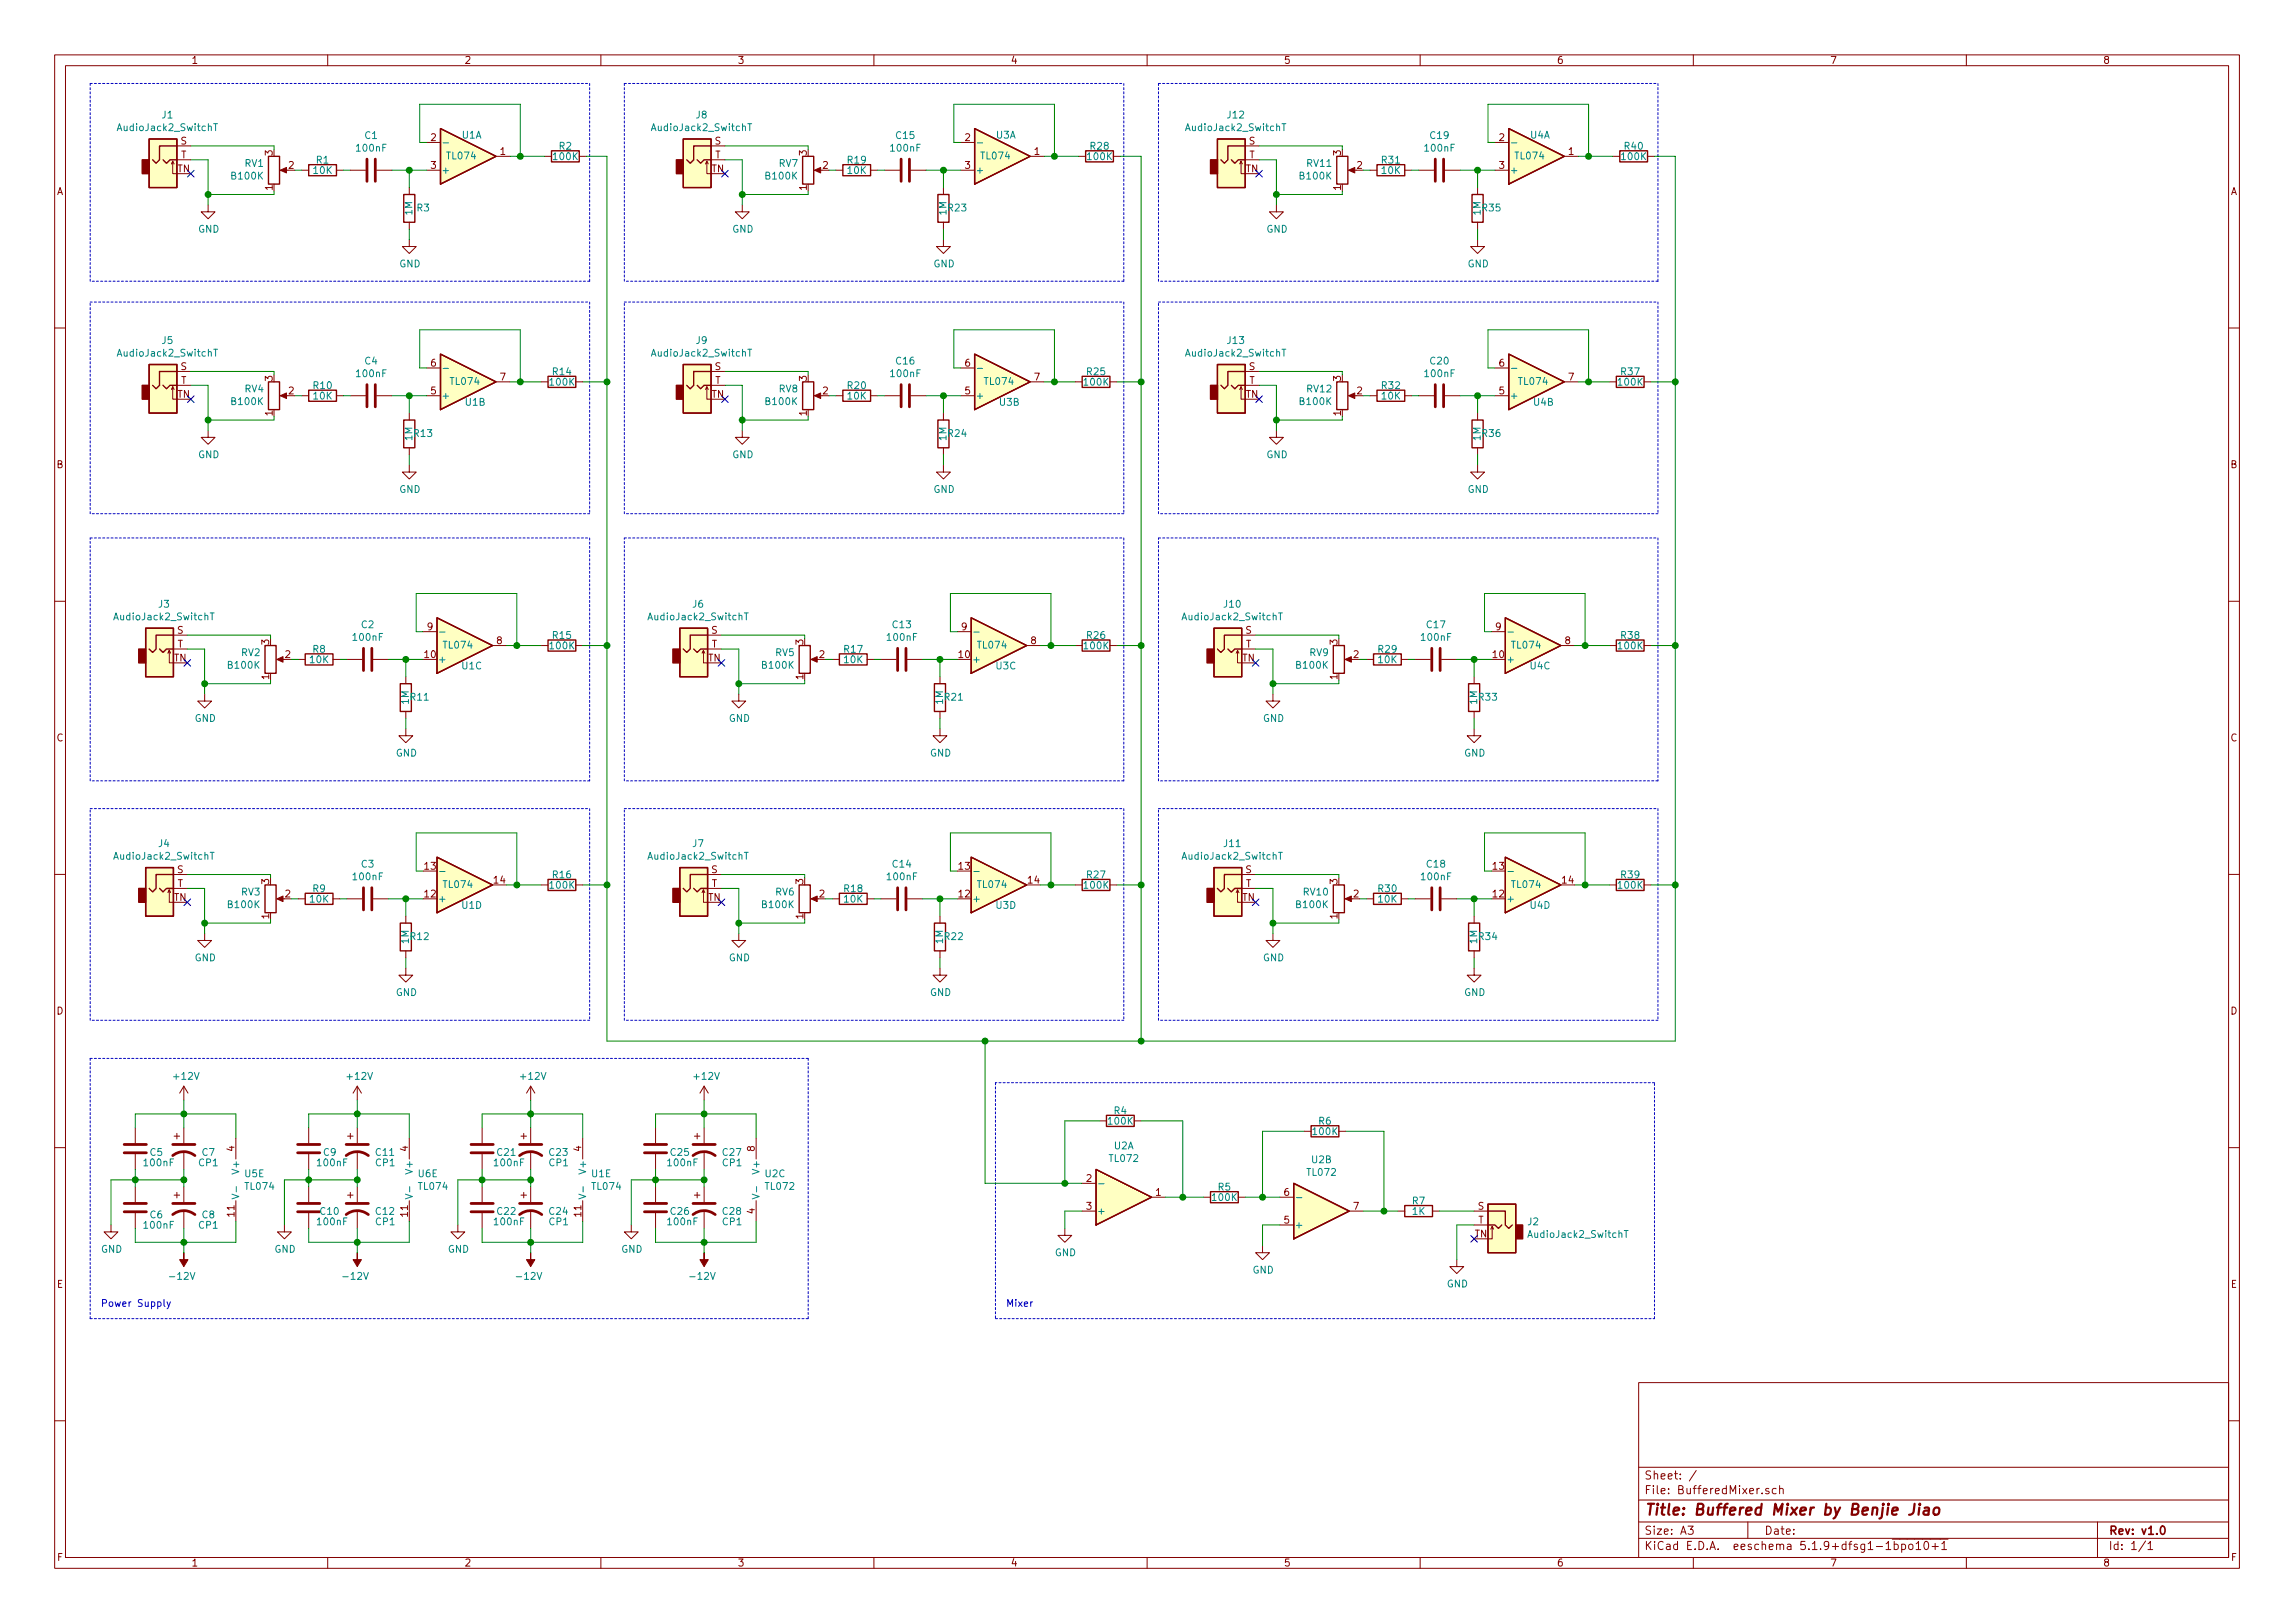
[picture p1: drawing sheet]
<svg xmlns="http://www.w3.org/2000/svg" width="420mm" height="297mm" viewBox="0 0 420 297" stroke-linecap="round" stroke-linejoin="round" font-family="sans-serif">
<defs><g id="words">
<text font-size="2.8" fill="#840000" x="301" y="277.3">Title: Buffered Mixer by Benjie Jiao</text>
<g font-size="2.1" fill="#840000">
<text x="301" y="273.5">File: BufferedMixer.sch</text>
<text x="301" y="270.8">Sheet: /</text>
<text x="301" y="280.9">Size: A3</text>
<text x="323" y="280.9">Date:</text>
<text x="386" y="280.9">Rev: v1.0</text>
<text x="301" y="283.7">KiCad E.D.A. eeschema 5.1.9+dfsg1-1bpo10+1</text>
<text x="386" y="283.7">Id: 1/1</text>
</g>
<g font-size="1.8" fill="#840000">
<text x="35" y="11.7">1</text>
<text x="85" y="11.7">2</text>
<text x="135" y="11.7">3</text>
<text x="185" y="11.7">4</text>
<text x="235" y="11.7">5</text>
<text x="285" y="11.7">6</text>
<text x="335" y="11.7">7</text>
<text x="385" y="11.7">8</text>
<text x="33.1" y="26.5">S</text>
<text x="33.1" y="29">T</text>
<text x="49.9" y="28.5" transform="rotate(-90 49.9 28.5)">3</text>
<text x="78.9" y="25.8">2</text>
<text x="91.6" y="28.4">1</text>
<text x="130.9" y="26.5">S</text>
<text x="130.9" y="29">T</text>
<text x="147.7" y="28.5" transform="rotate(-90 147.7 28.5)">3</text>
<text x="176.7" y="25.8">2</text>
<text x="189.4" y="28.4">1</text>
<text x="228.7" y="26.5">S</text>
<text x="228.7" y="29">T</text>
<text x="245.5" y="28.5" transform="rotate(-90 245.5 28.5)">3</text>
<text x="274.5" y="25.8">2</text>
<text x="287.2" y="28.4">1</text>
<text x="10.4" y="35.7">A</text>
<text x="32.5" y="31.5">TN</text>
<text x="49.9" y="34.8" transform="rotate(-90 49.9 34.8)">1</text>
<text x="52.9" y="30.9">2</text>
<text x="78.9" y="30.9">3</text>
<text x="130.3" y="31.5">TN</text>
<text x="147.7" y="34.8" transform="rotate(-90 147.7 34.8)">1</text>
<text x="150.6" y="30.9">2</text>
<text x="176.7" y="30.9">3</text>
<text x="228.1" y="31.5">TN</text>
<text x="245.5" y="34.8" transform="rotate(-90 245.5 34.8)">1</text>
<text x="248.4" y="30.9">2</text>
<text x="274.5" y="30.9">3</text>
<text x="408.4" y="35.7">A</text>
<text x="33.1" y="67.7">S</text>
<text x="33.1" y="70.3">T</text>
<text x="49.9" y="69.7" transform="rotate(-90 49.9 69.7)">3</text>
<text x="78.9" y="67.1">6</text>
<text x="91.6" y="69.6">7</text>
<text x="130.9" y="67.7">S</text>
<text x="130.9" y="70.3">T</text>
<text x="147.7" y="69.7" transform="rotate(-90 147.7 69.7)">3</text>
<text x="176.7" y="67.1">6</text>
<text x="189.4" y="69.6">7</text>
<text x="228.7" y="67.7">S</text>
<text x="228.7" y="70.3">T</text>
<text x="245.5" y="69.7" transform="rotate(-90 245.5 69.7)">3</text>
<text x="274.5" y="67.1">6</text>
<text x="287.2" y="69.6">7</text>
<text x="32.5" y="72.8">TN</text>
<text x="49.9" y="76.1" transform="rotate(-90 49.9 76.1)">1</text>
<text x="52.9" y="72.2">2</text>
<text x="78.9" y="72.2">5</text>
<text x="130.3" y="72.8">TN</text>
<text x="147.7" y="76.1" transform="rotate(-90 147.7 76.1)">1</text>
<text x="150.6" y="72.2">2</text>
<text x="176.7" y="72.2">5</text>
<text x="228.1" y="72.8">TN</text>
<text x="245.5" y="76.1" transform="rotate(-90 245.5 76.1)">1</text>
<text x="248.4" y="72.2">2</text>
<text x="274.5" y="72.2">5</text>
<text x="10.4" y="85.7">B</text>
<text x="408.4" y="85.7">B</text>
<text x="32.4" y="116">S</text>
<text x="32.5" y="118.5">T</text>
<text x="49.3" y="118" transform="rotate(-90 49.3 118)">3</text>
<text x="78.3" y="115.4">9</text>
<text x="91" y="117.9">8</text>
<text x="130.2" y="116">S</text>
<text x="130.3" y="118.5">T</text>
<text x="147.1" y="118" transform="rotate(-90 147.1 118)">3</text>
<text x="176" y="115.4">9</text>
<text x="188.7" y="117.9">8</text>
<text x="228" y="116">S</text>
<text x="228.1" y="118.5">T</text>
<text x="244.9" y="118" transform="rotate(-90 244.9 118)">3</text>
<text x="273.8" y="115.4">9</text>
<text x="286.5" y="117.9">8</text>
<text x="31.9" y="121.1">TN</text>
<text x="49.3" y="124.3" transform="rotate(-90 49.3 124.3)">1</text>
<text x="52.2" y="120.4">2</text>
<text x="77.8" y="120.4">10</text>
<text x="129.6" y="121.1">TN</text>
<text x="147.1" y="124.3" transform="rotate(-90 147.1 124.3)">1</text>
<text x="150" y="120.4">2</text>
<text x="175.6" y="120.4">10</text>
<text x="227.4" y="121.1">TN</text>
<text x="244.9" y="124.3" transform="rotate(-90 244.9 124.3)">1</text>
<text x="247.8" y="120.4">2</text>
<text x="273.4" y="120.4">10</text>
<text x="10.4" y="135.7">C</text>
<text x="408.4" y="135.7">C</text>
<text x="32.4" y="159.8">S</text>
<text x="49.3" y="161.8" transform="rotate(-90 49.3 161.8)">3</text>
<text x="77.8" y="159.2">13</text>
<text x="90.5" y="161.7">14</text>
<text x="130.2" y="159.8">S</text>
<text x="147.1" y="161.8" transform="rotate(-90 147.1 161.8)">3</text>
<text x="175.6" y="159.2">13</text>
<text x="188.3" y="161.7">14</text>
<text x="228" y="159.8">S</text>
<text x="244.9" y="161.8" transform="rotate(-90 244.9 161.8)">3</text>
<text x="273.4" y="159.2">13</text>
<text x="286.1" y="161.7">14</text>
<text x="31.9" y="164.9">TN</text>
<text x="32.5" y="162.3">T</text>
<text x="52.2" y="164.2">2</text>
<text x="77.8" y="164.2">12</text>
<text x="129.6" y="164.9">TN</text>
<text x="130.3" y="162.3">T</text>
<text x="150" y="164.2">2</text>
<text x="175.6" y="164.2">12</text>
<text x="227.4" y="164.9">TN</text>
<text x="228.1" y="162.3">T</text>
<text x="247.8" y="164.2">2</text>
<text x="273.4" y="164.2">12</text>
<text x="49.3" y="168.2" transform="rotate(-90 49.3 168.2)">1</text>
<text x="147.1" y="168.2" transform="rotate(-90 147.1 168.2)">1</text>
<text x="244.9" y="168.2" transform="rotate(-90 244.9 168.2)">1</text>
<text x="10.4" y="185.7">D</text>
<text x="408.4" y="185.7">D</text>
<text x="42.9" y="210.7" transform="rotate(-90 42.9 210.7)">4</text>
<text x="74.7" y="210.7" transform="rotate(-90 74.7 210.7)">4</text>
<text x="106.4" y="210.7" transform="rotate(-90 106.4 210.7)">4</text>
<text x="138.2" y="210.7" transform="rotate(-90 138.2 210.7)">8</text>
<text x="198.9" y="216.3">2</text>
<text x="198.9" y="221.4">3</text>
<text x="211.6" y="218.9">1</text>
<text x="235.1" y="218.9">6</text>
<text x="247.8" y="221.4">7</text>
<text x="270.6" y="221.4">S</text>
<text x="42.9" y="222.6" transform="rotate(-90 42.9 222.6)">11</text>
<text x="74.7" y="222.6" transform="rotate(-90 74.7 222.6)">11</text>
<text x="106.4" y="222.6" transform="rotate(-90 106.4 222.6)">11</text>
<text x="138.2" y="222.1" transform="rotate(-90 138.2 222.1)">4</text>
<text x="235.1" y="223.9">5</text>
<text x="270" y="226.5">TN</text>
<text x="270.6" y="223.9">T</text>
<text x="10.4" y="235.7">E</text>
<text x="408.4" y="235.7">E</text>
<text x="10.5" y="285.7">F</text>
<text x="35" y="286.7">1</text>
<text x="85" y="286.7">2</text>
<text x="135" y="286.7">3</text>
<text x="185" y="286.7">4</text>
<text x="235" y="286.7">5</text>
<text x="285" y="286.7">6</text>
<text x="335" y="286.7">7</text>
<text x="385" y="286.7">8</text>
<text x="408.5" y="285.7">F</text>
</g>
<g font-size="1.8" fill="#008484">
<text x="21.8" y="24">AudioJack2_SwitchT</text>
<text x="29.7" y="21.7">J1</text>
<text x="119.6" y="24">AudioJack2_SwitchT</text>
<text x="127.5" y="21.7">J8</text>
<text x="217.4" y="24">AudioJack2_SwitchT</text>
<text x="224.8" y="21.7">J12</text>
<text x="57.9" y="29.9">R1</text>
<text x="65.4" y="27.7">100nF</text>
<text x="66.8" y="25.4">C1</text>
<text x="81.9" y="29.2">TL074</text>
<text x="84.6" y="25.4">U1A</text>
<text x="101.4" y="29.3">100K</text>
<text x="102.4" y="27.4">R2</text>
<text x="155.2" y="29.9">R19</text>
<text x="163.2" y="27.7">100nF</text>
<text x="164.1" y="25.4">C15</text>
<text x="179.7" y="29.2">TL074</text>
<text x="182.4" y="25.4">U3A</text>
<text x="199.2" y="29.3">100K</text>
<text x="199.7" y="27.4">R28</text>
<text x="253" y="29.9">R31</text>
<text x="261" y="27.7">100nF</text>
<text x="261.9" y="25.4">C19</text>
<text x="277.5" y="29.2">TL074</text>
<text x="280.2" y="25.4">U4A</text>
<text x="297" y="29.3">100K</text>
<text x="297.5" y="27.4">R40</text>
<text x="42.5" y="32.9">B100K</text>
<text x="44.9" y="30.5">RV1</text>
<text x="57.4" y="31.8">10K</text>
<text x="80.8" y="31.8">+</text>
<text x="140.3" y="32.9">B100K</text>
<text x="142.6" y="30.5">RV7</text>
<text x="155.2" y="31.8">10K</text>
<text x="178.6" y="31.8">+</text>
<text x="238.1" y="32.9">B100K</text>
<text x="239.3" y="30.5">RV11</text>
<text x="253" y="31.8">10K</text>
<text x="276.4" y="31.8">+</text>
<text x="75.5" y="39.4" transform="rotate(-90 75.5 39.4)">1M</text>
<text x="76.4" y="38.7">R3</text>
<text x="173.3" y="39.4" transform="rotate(-90 173.3 39.4)">1M</text>
<text x="173.6" y="38.7">R23</text>
<text x="271.1" y="39.4" transform="rotate(-90 271.1 39.4)">1M</text>
<text x="271.4" y="38.7">R35</text>
<text x="36.3" y="42.6">GND</text>
<text x="134.1" y="42.6">GND</text>
<text x="231.9" y="42.6">GND</text>
<text x="73.1" y="48.9">GND</text>
<text x="170.9" y="48.9">GND</text>
<text x="268.7" y="48.9">GND</text>
<text x="21.8" y="65.3">AudioJack2_SwitchT</text>
<text x="29.7" y="63">J5</text>
<text x="119.6" y="65.3">AudioJack2_SwitchT</text>
<text x="127.5" y="63">J9</text>
<text x="217.4" y="65.3">AudioJack2_SwitchT</text>
<text x="224.8" y="63">J13</text>
<text x="44.9" y="71.8">RV4</text>
<text x="57.4" y="71.2">R10</text>
<text x="65.4" y="69">100nF</text>
<text x="66.8" y="66.7">C4</text>
<text x="82.5" y="70.4">TL074</text>
<text x="100.8" y="70.6">100K</text>
<text x="101.2" y="68.7">R14</text>
<text x="142.6" y="71.8">RV8</text>
<text x="155.2" y="71.2">R20</text>
<text x="163.2" y="69">100nF</text>
<text x="164.1" y="66.7">C16</text>
<text x="180.3" y="70.4">TL074</text>
<text x="198.6" y="70.6">100K</text>
<text x="199" y="68.7">R25</text>
<text x="239.3" y="71.8">RV12</text>
<text x="253" y="71.2">R32</text>
<text x="261" y="69">100nF</text>
<text x="261.9" y="66.7">C20</text>
<text x="278.1" y="70.4">TL074</text>
<text x="296.3" y="70.6">100K</text>
<text x="296.8" y="68.7">R37</text>
<text x="42.5" y="74.1">B100K</text>
<text x="57.4" y="73.1">10K</text>
<text x="80.8" y="73.1">+</text>
<text x="85.2" y="74.3">U1B</text>
<text x="140.3" y="74.1">B100K</text>
<text x="155.2" y="73.1">10K</text>
<text x="178.6" y="73.1">+</text>
<text x="183" y="74.3">U3B</text>
<text x="238.1" y="74.1">B100K</text>
<text x="253" y="73.1">10K</text>
<text x="276.4" y="73.1">+</text>
<text x="280.8" y="74.3">U4B</text>
<text x="36.3" y="83.9">GND</text>
<text x="75.5" y="80.6" transform="rotate(-90 75.5 80.6)">1M</text>
<text x="75.8" y="80">R13</text>
<text x="134.1" y="83.9">GND</text>
<text x="173.3" y="80.6" transform="rotate(-90 173.3 80.6)">1M</text>
<text x="173.6" y="80">R24</text>
<text x="231.9" y="83.9">GND</text>
<text x="271.1" y="80.6" transform="rotate(-90 271.1 80.6)">1M</text>
<text x="271.4" y="80">R36</text>
<text x="73.1" y="90.2">GND</text>
<text x="170.9" y="90.2">GND</text>
<text x="268.7" y="90.2">GND</text>
<text x="21.2" y="113.5">AudioJack2_SwitchT</text>
<text x="29.1" y="111.2">J3</text>
<text x="119" y="113.5">AudioJack2_SwitchT</text>
<text x="126.8" y="111.2">J6</text>
<text x="216.8" y="113.5">AudioJack2_SwitchT</text>
<text x="224.1" y="111.2">J10</text>
<text x="57.3" y="119.5">R8</text>
<text x="64.8" y="117.3">100nF</text>
<text x="66.2" y="115">C2</text>
<text x="81.3" y="118.7">TL074</text>
<text x="100.8" y="118.8">100K</text>
<text x="101.2" y="116.9">R15</text>
<text x="154.6" y="119.5">R17</text>
<text x="162.6" y="117.3">100nF</text>
<text x="163.5" y="115">C13</text>
<text x="179.1" y="118.7">TL074</text>
<text x="198.6" y="118.8">100K</text>
<text x="199" y="116.9">R26</text>
<text x="252.4" y="119.5">R29</text>
<text x="260.3" y="117.3">100nF</text>
<text x="261.3" y="115">C17</text>
<text x="276.9" y="118.7">TL074</text>
<text x="296.3" y="118.8">100K</text>
<text x="296.8" y="116.9">R38</text>
<text x="41.9" y="122.4">B100K</text>
<text x="44.2" y="120.1">RV2</text>
<text x="56.8" y="121.4">10K</text>
<text x="80.1" y="121.3">+</text>
<text x="84.6" y="122.5">U1C</text>
<text x="139.6" y="122.4">B100K</text>
<text x="142" y="120.1">RV5</text>
<text x="154.6" y="121.4">10K</text>
<text x="177.9" y="121.3">+</text>
<text x="182.4" y="122.5">U3C</text>
<text x="237.4" y="122.4">B100K</text>
<text x="239.8" y="120.1">RV9</text>
<text x="252.4" y="121.4">10K</text>
<text x="275.7" y="121.3">+</text>
<text x="280.2" y="122.5">U4C</text>
<text x="74.9" y="128.9" transform="rotate(-90 74.9 128.9)">1M</text>
<text x="75.2" y="128.2">R11</text>
<text x="172.6" y="128.9" transform="rotate(-90 172.6 128.9)">1M</text>
<text x="173" y="128.2">R21</text>
<text x="270.4" y="128.9" transform="rotate(-90 270.4 128.9)">1M</text>
<text x="270.8" y="128.2">R33</text>
<text x="35.6" y="132.1">GND</text>
<text x="133.4" y="132.1">GND</text>
<text x="231.2" y="132.1">GND</text>
<text x="72.5" y="138.5">GND</text>
<text x="170.3" y="138.5">GND</text>
<text x="268" y="138.5">GND</text>
<text x="29.1" y="155">J4</text>
<text x="126.8" y="155">J7</text>
<text x="224.1" y="155">J11</text>
<text x="21.2" y="157.3">AudioJack2_SwitchT</text>
<text x="64.8" y="161.1">100nF</text>
<text x="66.2" y="158.8">C3</text>
<text x="101.2" y="160.7">R16</text>
<text x="119" y="157.3">AudioJack2_SwitchT</text>
<text x="162.6" y="161.1">100nF</text>
<text x="163.5" y="158.8">C14</text>
<text x="199" y="160.7">R27</text>
<text x="216.8" y="157.3">AudioJack2_SwitchT</text>
<text x="260.3" y="161.1">100nF</text>
<text x="261.3" y="158.8">C18</text>
<text x="296.8" y="160.7">R39</text>
<text x="41.9" y="166.2">B100K</text>
<text x="44.2" y="163.9">RV3</text>
<text x="56.8" y="165.2">10K</text>
<text x="57.3" y="163.3">R9</text>
<text x="80.1" y="165.1">+</text>
<text x="81.3" y="162.5">TL074</text>
<text x="84.6" y="166.3">U1D</text>
<text x="100.8" y="162.6">100K</text>
<text x="139.6" y="166.2">B100K</text>
<text x="142" y="163.9">RV6</text>
<text x="154.6" y="163.3">R18</text>
<text x="154.6" y="165.2">10K</text>
<text x="177.9" y="165.1">+</text>
<text x="179.1" y="162.5">TL074</text>
<text x="182.4" y="166.3">U3D</text>
<text x="198.6" y="162.6">100K</text>
<text x="237.4" y="166.2">B100K</text>
<text x="238.7" y="163.9">RV10</text>
<text x="252.4" y="163.3">R30</text>
<text x="252.4" y="165.2">10K</text>
<text x="275.7" y="165.1">+</text>
<text x="276.9" y="162.5">TL074</text>
<text x="280.2" y="166.3">U4D</text>
<text x="296.3" y="162.6">100K</text>
<text x="74.9" y="172.7" transform="rotate(-90 74.9 172.7)">1M</text>
<text x="75.2" y="172">R12</text>
<text x="172.6" y="172.7" transform="rotate(-90 172.6 172.7)">1M</text>
<text x="173" y="172">R22</text>
<text x="270.4" y="172.7" transform="rotate(-90 270.4 172.7)">1M</text>
<text x="270.8" y="172">R34</text>
<text x="35.6" y="175.9">GND</text>
<text x="133.4" y="175.9">GND</text>
<text x="231.2" y="175.9">GND</text>
<text x="72.5" y="182.3">GND</text>
<text x="170.3" y="182.3">GND</text>
<text x="268" y="182.3">GND</text>
<text x="32" y="197.6">+12V</text>
<text x="63.7" y="197.6">+12V</text>
<text x="95.5" y="197.6">+12V</text>
<text x="127.2" y="197.6">+12V</text>
<text x="204" y="203.9">R4</text>
<text x="203" y="205.8">100K</text>
<text x="240.5" y="207.7">100K</text>
<text x="241.5" y="205.8">R6</text>
<text x="26.5" y="213.4">100nF</text>
<text x="27.5" y="211.5">C5</text>
<text x="36.4" y="213.4">CP1</text>
<text x="37" y="211.5">C7</text>
<text x="43.8" y="214.5" transform="rotate(-90 43.8 214.5)">V+</text>
<text x="44.9" y="215.5">U5E</text>
<text x="58.2" y="213.4">100nF</text>
<text x="59.3" y="211.5">C9</text>
<text x="68.8" y="213.4">CP1</text>
<text x="68.9" y="211.5">C11</text>
<text x="75.6" y="214.5" transform="rotate(-90 75.6 214.5)">V+</text>
<text x="76.6" y="215.5">U6E</text>
<text x="90.6" y="213.4">100nF</text>
<text x="91.1" y="211.5">C21</text>
<text x="100.6" y="213.4">CP1</text>
<text x="100.6" y="211.5">C23</text>
<text x="107.3" y="214.5" transform="rotate(-90 107.3 214.5)">V+</text>
<text x="108.4" y="215.5">U1E</text>
<text x="122.4" y="213.4">100nF</text>
<text x="122.8" y="211.5">C25</text>
<text x="132.3" y="213.4">CP1</text>
<text x="132.4" y="211.5">C27</text>
<text x="139.1" y="214.5" transform="rotate(-90 139.1 214.5)">V+</text>
<text x="140.1" y="215.5">U2C</text>
<text x="203.2" y="212.7">TL072</text>
<text x="204" y="210.3">U2A</text>
<text x="239.4" y="215.2">TL072</text>
<text x="240.2" y="212.9">U2B</text>
<text x="45" y="217.8">TL074</text>
<text x="76.7" y="217.8">TL074</text>
<text x="108.5" y="217.8">TL074</text>
<text x="140.2" y="217.8">TL072</text>
<text x="222" y="219.8">100K</text>
<text x="223" y="217.9">R5</text>
<text x="258.6" y="220.4">R7</text>
<text x="26.5" y="224.9">100nF</text>
<text x="27.5" y="223">C6</text>
<text x="36.4" y="224.9">CP1</text>
<text x="37" y="223">C8</text>
<text x="58.2" y="224.2">100nF</text>
<text x="58.7" y="222.3">C10</text>
<text x="68.8" y="224.2">CP1</text>
<text x="68.9" y="222.3">C12</text>
<text x="90.6" y="224.2">100nF</text>
<text x="91.1" y="222.3">C22</text>
<text x="100.6" y="224.2">CP1</text>
<text x="100.6" y="222.3">C24</text>
<text x="122.4" y="224.2">100nF</text>
<text x="122.8" y="222.3">C26</text>
<text x="132.3" y="224.2">CP1</text>
<text x="132.4" y="222.3">C28</text>
<text x="200.8" y="222.3">+</text>
<text x="237" y="224.8">+</text>
<text x="258.6" y="222.3">1K</text>
<text x="279.7" y="224.2">J2</text>
<text x="280.1" y="226.6">AudioJack2_SwitchT</text>
<text x="18.5" y="229.3">GND</text>
<text x="50.2" y="229.3">GND</text>
<text x="82" y="229.3">GND</text>
<text x="113.7" y="229.3">GND</text>
<text x="193.1" y="229.9">GND</text>
<text x="229.3" y="233.1">GND</text>
<text x="31.4" y="234.2">-12V</text>
<text x="63.2" y="234.2">-12V</text>
<text x="94.9" y="234.2">-12V</text>
<text x="126.7" y="234.2">-12V</text>
<text x="264.9" y="235.6">GND</text>
</g>
<g font-size="1.8" fill="#0000c2">
<text x="18.4" y="239.2">Power Supply</text>
<text x="184.1" y="239.2">Mixer</text>
</g>
</g></defs>
<g fill="none" stroke="#840000" stroke-width=".18">
<path d="M10 10h400v277h-400zM12 12h396v273.1h-396zM60 10v2M110 10v2M160 10v2M210 10v2M260 10v2M310 10v2M360 10v2M31.4 30l.2-.5v2.3h.8M31.6 29.5l.3 .5M32.4 26.7h2.5"/>
<path d="M32.4 29.2h2.5M38.1 37.5v1.3h1.3l-1.3 1.2-1.3-1.2h1.3M51.7 31.2h1M55.2 31.2h1.3M61.6 31.2h1.3M64.1 31.2h2.8M69 31.2h2.8M74.9 34.3v1.3M78.1 31.2h2.5M78.1 26.1h2.5M90.8 28.6h2.5M99.7 28.6h1.3"/>
<path d="M106 28.6h1.3M129.2 30l.2-.5v2.3h.8M129.4 29.5l.3 .5M130.2 26.7h2.5M130.2 29.2h2.5M135.9 37.5v1.3h1.3l-1.3 1.2-1.3-1.2h1.3M149.5 31.2h1M153 31.2h1.3M159.4 31.2h1.3M161.9 31.2h2.8M166.8 31.2h2.7M172.7 34.3v1.3"/>
<path d="M175.9 31.2h2.5M175.9 26.1h2.5M188.6 28.6h2.5M197.5 28.6h1.3M203.8 28.6h1.3M226.9 30l.3-.5v2.3h.8M227.2 29.5l.3 .5M228 26.7h2.5M228 29.2h2.5M233.7 37.5v1.3h1.2l-1.2 1.2-1.3-1.2h1.3M247.3 31.2h1M250.8 31.2h1.3"/>
<path d="M257.2 31.2h1.2M259.7 31.2h2.8M264.5 31.2h2.8M270.5 34.3v1.3M273.7 31.2h2.5M273.7 26.1h2.5M286.4 28.6h2.5M295.3 28.6h1.2M301.6 28.6h1.3M74.9 43.9v1.2h1.3l-1.3 1.3-1.2-1.3h1.2M74.9 40.7v1.2M172.7 43.9v1.2h1.3l-1.3 1.3-1.3-1.3h1.3"/>
<path d="M172.7 40.7v1.2M270.5 43.9v1.2h1.3l-1.3 1.3-1.3-1.3h1.3M270.5 40.7v1.2M10 60h2M31.4 71.3l.2-.5v2.3h.8M31.6 70.8l.3 .5M32.4 68h2.5M32.4 70.5h2.5M38.1 78.8v1.2h1.3l-1.3 1.3-1.3-1.3h1.3M51.7 72.4h1M55.2 72.4h1.3M61.6 72.4h1.3"/>
<path d="M64.1 72.4h2.8M69 72.4h2.8M74.9 75.6v1.3M78.1 72.4h2.5M78.1 67.3h2.5M90.8 69.9h2.5M99.1 69.9h1.2M105.4 69.9h1.3M129.2 71.3l.2-.5v2.3h.8M129.4 70.8l.3 .5M130.2 68h2.5M130.2 70.5h2.5"/>
<path d="M135.9 78.8v1.2h1.3l-1.3 1.3-1.3-1.3h1.3M149.5 72.4h1M153 72.4h1.3M159.4 72.4h1.3M161.9 72.4h2.8M166.8 72.4h2.7M172.7 75.6v1.3M175.9 72.4h2.5M175.9 67.3h2.5M188.6 69.9h2.5M196.8 69.9h1.3M203.2 69.9h1.3"/>
<path d="M226.9 71.3l.3-.5v2.3h.8M227.2 70.8l.3 .5M228 68h2.5M228 70.5h2.5M233.7 78.8v1.2h1.2l-1.2 1.3-1.3-1.3h1.3M247.3 72.4h1M250.8 72.4h1.3M257.2 72.4h1.2M259.7 72.4h2.8M264.5 72.4h2.8M270.5 75.6v1.3M273.7 72.4h2.5"/>
<path d="M273.7 67.3h2.5M286.4 69.9h2.5M294.6 69.9h1.3M301 69.9h1.3M408 60h2M74.9 85.1v1.3h1.3l-1.3 1.3-1.2-1.3h1.2M74.9 82v1.2M172.7 85.1v1.3h1.3l-1.3 1.3-1.3-1.3h1.3M172.7 82v1.2M270.5 85.1v1.3h1.3l-1.3 1.3-1.3-1.3h1.3M270.5 82v1.2M10 110h2"/>
<path d="M30.7 119.5l.3-.5v2.3h.7M31 119l.2 .5M31.7 116.2h2.6M31.7 118.8h2.6M77.5 115.6h2.5M90.2 118.1h2.5M99.1 118.1h1.2M105.4 118.1h1.3M128.5 119.5l.3-.5v2.3h.7M128.8 119l.2 .5M129.5 116.2h2.6M129.5 118.8h2.6"/>
<path d="M175.3 115.6h2.5M188 118.1h2.5M196.8 118.1h1.3M203.2 118.1h1.3M226.3 119.5l.3-.5v2.3h.7M226.6 119l.2 .5M227.3 116.2h2.6M227.3 118.8h2.6M273 115.6h2.6M285.7 118.1h2.6M294.6 118.1h1.3M301 118.1h1.3"/>
<path d="M408 110h2M37.5 127v1.3h1.2l-1.2 1.3-1.3-1.3h1.3M51.1 120.7h1M54.6 120.7h1.3M61 120.7h1.2M63.5 120.7h2.8M68.3 120.7h2.8M74.3 133.4v1.3h1.3l-1.3 1.2-1.3-1.2h1.3M74.3 123.9v1.2M74.3 130.2v1.3M135.3 127v1.3h1.2l-1.2 1.3-1.3-1.3h1.3M148.8 120.7h1.1"/>
<path d="M152.4 120.7h1.3M158.7 120.7h1.3M161.3 120.7h2.8M166.1 120.7h2.8M172.1 133.4v1.3h1.3l-1.3 1.2-1.3-1.2h1.3M172.1 123.9v1.2M172.1 130.2v1.3M233 127v1.3h1.3l-1.3 1.3-1.2-1.3h1.2M246.6 120.7h1M250.2 120.7h1.3M256.5 120.7h1.3M259.1 120.7h2.8"/>
<path d="M263.9 120.7h2.8M269.9 133.4v1.3h1.2l-1.2 1.2-1.3-1.2h1.3M269.9 123.9v1.2M269.9 130.2v1.3M10 160h2M30.7 163.4l.3-.5v2.2h.7M31 162.9l.2 .5M31.7 160.1h2.6M31.7 162.6h2.6M37.5 170.9v1.2h1.2l-1.2 1.3-1.3-1.3h1.3M51.1 164.5h1M54.6 164.5h1.3"/>
<path d="M61 164.5h1.2M63.5 164.5h2.8M68.3 164.5h2.8M74.3 177.2v1.3h1.3l-1.3 1.2-1.3-1.2h1.3M74.3 167.7v1.2M74.3 174v1.3M99.1 162h1.2M105.4 162h1.3M128.5 163.4l.3-.5v2.2h.7M128.8 162.9l.2 .5M129.5 160.1h2.6M129.5 162.6h2.6"/>
<path d="M135.3 170.9v1.2h1.2l-1.2 1.3-1.3-1.3h1.3M148.8 164.5h1.1M152.4 164.5h1.3M158.7 164.5h1.3M161.3 164.5h2.8M166.1 164.5h2.8M172.1 177.2v1.3h1.3l-1.3 1.2-1.3-1.2h1.3M172.1 167.7v1.2M172.1 174v1.3M196.8 162h1.3M203.2 162h1.3M226.3 163.4l.3-.5v2.2h.7"/>
<path d="M226.6 162.9l.2 .5M227.3 160.1h2.6M227.3 162.6h2.6M233 170.9v1.2h1.3l-1.3 1.3-1.2-1.3h1.2M246.6 164.5h1M250.2 164.5h1.3M256.5 164.5h1.3M259.1 164.5h2.8M263.9 164.5h2.8M269.9 177.2v1.3h1.2l-1.2 1.2-1.3-1.2h1.3M269.9 167.7v1.2M269.9 174v1.3"/>
<path d="M294.6 162h1.3M301 162h1.3M408 160h2M33.7 198.8l-.8 1.3M33.7 198.8v2.5M33.7 198.8l.7 1.3M65.4 198.8l-.8 1.3M65.4 198.8v2.5M65.4 198.8l.8 1.3M97.2 198.8l-.8 1.3M97.2 198.8v2.5M97.2 198.8l.7 1.3"/>
<path d="M128.9 198.8l-.8 1.3M128.9 198.8v2.5M128.9 198.8l.8 1.3M10 210h2M24.8 206.4v2.8M24.8 211.2v2.8M24.8 217.2v2.8M31.9 207.9h1M31.9 218.7h1M32.4 207.4v1M32.4 218.2v1M33.7 206.4v2.8"/>
<path d="M33.7 210.7v3.3M33.7 217.2v2.8M43.2 208.3v3.8M43.2 219.7v3.9M56.5 206.4v2.8M56.5 211.2v2.8M56.5 217.2v2.8M63.6 207.9h1M63.6 218.7h1M64.1 207.4v1M64.1 218.2v1M65.4 206.4v2.8"/>
<path d="M65.4 210.7v3.3M65.4 217.2v2.8M74.9 208.3v3.8M74.9 219.7v3.9M88.3 206.4v2.8M88.3 211.2v2.8M88.3 217.2v2.8M95.4 207.9h1M95.4 218.7h1M95.9 207.4v1M95.9 218.2v1M97.2 206.4v2.8"/>
<path d="M97.2 210.7v3.3M97.2 217.2v2.8M106.7 208.3v3.8M106.7 219.7v3.9M120 206.4v2.8M120 211.2v2.8M120 217.2v2.8M127.1 207.9h1M127.1 218.7h1M127.6 207.4v1M127.6 218.2v1M128.9 206.4v2.8"/>
<path d="M128.9 210.7v3.3M128.9 217.2v2.8M138.4 208.3v3.8M138.4 219.7v3.9M198.1 216.6h2.6M201.3 205.1h1.3M207.6 205.1h1.3M210.8 219.1h2.6M220.3 219.1h1.3M226.7 219.1h1.3M234.3 219.1h2.6M238.8 207h1.2"/>
<path d="M245.1 207h1.3M408 210h2M20.3 224.2v1.3h1.3l-1.3 1.2-1.3-1.2h1.3M24.8 222v2.8M33.7 221.5v3.3M52.1 224.2v1.3h1.2l-1.2 1.2-1.3-1.2h1.3M56.5 222v2.8M65.4 221.5v3.3M83.8 224.2v1.3h1.3l-1.3 1.2-1.3-1.2h1.3M88.3 222v2.8M97.2 221.5v3.3M115.6 224.2v1.3h1.2l-1.2 1.2-1.3-1.2h1.3"/>
<path d="M120 222v2.8M128.9 221.5v3.3M194.9 224.8v1.3h1.3l-1.3 1.3-1.2-1.3h1.2M198.1 221.7h2.6M231.1 228v1.3h1.3l-1.3 1.2-1.2-1.2h1.2M234.3 224.2h2.6M247 221.7h2.6M255.9 221.7h1.3M262.3 221.7h1.2M266.7 230.5v1.3h1.3l-1.3 1.3-1.3-1.3h1.3M269.9 221.7h2.5M269.9 224.2h2.5"/>
<path d="M273.2 224.4l-.3 .6M273.4 225l-.2-.6v2.3h-.8M300 253h108v32.1h-108zM10 260h2M300 278.5h108M300 274.5h108M300 268.5h108M309 279.3h1l-.5 .6 .4 .1v.7l-.2 .1-.7-.1M310.5 269.1l-1.2 2M320 278.5v3M323.8 272.5a.37 .37 0 0 0-.6 .1l.1 .2 .5 .2 .1 .1-.2 .3-.5-.1M325.2 272.5l-.5-.1-.2 .3v.6l.2 .1 .5-.1"/>
<path d="M325.8 272.5h.1a.37 .37 0 0 1 .6 .1v.8M325.8 271.9v1.5M384 278.5v6.6M408 260h2M60 285.1v1.9M110 285.1v1.9M160 285.1v1.9M210 285.1v1.9M260 285.1v1.9M300 281.5h108M310 285.1v1.9M345.3 283.6h.9"/>
<path d="M346.4 281.7h10.2M346.8 282.7l.4-.1 .3 .3-.1 .6-.2 .1-.4-.1M346.8 282.1v1.5M348.2 282.7l.4-.1 .3 .3-.1 .6-.2 .1-.4-.1M348.2 282.6v1.5M349.5 282.7l.2-.1 .4 .1 .1 .6-.1 .2-.4 .1-.2-.1zM350.8 282.5l.4-.4v1.5M350.8 283.6h.8M352.4 282.2l.2-.1a.8 .8 0 0 1 .5 .8 .8 .8 0 0 1-.5 .7 1 1 0 0 1-.2-1.4zM353.7 283h1.2M354.3 282.5v1.1M355.5 282.5l.4-.4v1.5"/>
<path d="M355.5 283.6h.9M360 285.1v1.9M392.8 282l-1.3 2M393.2 282.5l.5-.4v1.5M393.2 283.6h.9"/>
</g>
<path d="M395.7 279.5l.2-.2a.81 .81 0 0 1 .6 .6 .81 .81 0 0 1-.3 .8l-.2 .1a.79 .79 0 0 1-.3-1.3z" fill="none" stroke="#840000" stroke-width=".3"/>
<path d="M350.5 275.2l-.2 1.5a.78 .78 0 0 1-.8 .5M351.4 275.9l-.2 1.3M351.5 275.2l-.1 .1 .1 .1v-.2v.2M352.3 276h.8l-.1 1.2M353.2 276.4l-.7 .1a.4 .4 0 0 0-.4 .3 .4 .4 0 0 0 .3 .4l.7-.1M354.2 276.1a.51 .51 0 0 1 .5-.2 .51 .51 0 0 1 .4 .4l-.1 .5a.54 .54 0 0 1-.5 .4 .54 .54 0 0 1-.6-.4z" fill="none" stroke="#840000" stroke-width=".41"/>
<g fill="none" stroke="#840000" stroke-width=".51">
<path d="M67.2 29.1v4.1M68.7 29.1v4.1M165 29.1v4.1M166.5 29.1v4.1M262.8 29.1v4.1M264.3 29.1v4.1M67.2 70.4v4.1M68.7 70.4v4.1M165 70.4v4.1M166.5 70.4v4.1M262.8 70.4v4.1M264.3 70.4v4.1"/>
<path d="M66.5 118.7v4M68.1 118.7v4M164.3 118.7v4M165.9 118.7v4M262.1 118.7v4M263.7 118.7v4M66.5 162.5v4M68.1 162.5v4M164.3 162.5v4M165.9 162.5v4M262.1 162.5v4M263.7 162.5v4"/>
<path d="M22.7 209.5h4.1M22.7 211h4.1M31.6 211.5a3.3 3.3 0 0 1 4.1 0M31.6 209.5h4.1M54.5 209.5h4M54.5 211h4M63.4 211.5a3.3 3.3 0 0 1 4 0M63.4 209.5h4M86.2 209.5h4.1M86.2 211h4.1M95.1 211.5a3.3 3.3 0 0 1 4.1 0M95.1 209.5h4.1"/>
<path d="M118 209.5h4M118 211h4M126.9 211.5a3.3 3.3 0 0 1 4 0M126.9 209.5h4M22.7 221.8h4.1M22.7 220.3h4.1M31.6 222.3a3.3 3.3 0 0 1 4.1 0M31.6 220.3h4.1M54.5 221.8h4M54.5 220.3h4M63.4 222.3a3.3 3.3 0 0 1 4 0M63.4 220.3h4"/>
<path d="M86.2 221.8h4.1M86.2 220.3h4.1M95.1 222.3a3.3 3.3 0 0 1 4.1 0M95.1 220.3h4.1M118 221.8h4M118 220.3h4M126.9 222.3a3.3 3.3 0 0 1 4 0M126.9 220.3h4"/>
</g>
<g fill="none" stroke="#840000" stroke-width=".25">
<path d="M27.3 25.4h5.1v8.9h-5.1zM29.8 29.2l.7 .7 .6-.7h1.3M32.4 26.7h-3.2v2.5l-.6 .7-.7-.7M49.1 28.6h2.1v5.1h-2.1zM56.5 30.1h5.1v2.1h-5.1zM73.9 35.6h2v5.1h-2zM80.6 23.5l10.2 5.1-10.2 5.1zM101 27.6h5v2h-5zM125.1 25.4h5.1v8.9h-5.1zM127.6 29.2l.7 .7 .6-.7h1.3M130.2 26.7h-3.2v2.5l-.6 .7-.7-.7M146.9 28.6h2.1v5.1h-2.1z"/>
<path d="M154.3 30.1h5.1v2.1h-5.1zM171.7 35.6h2v5.1h-2zM178.4 23.5l10.2 5.1-10.2 5.1zM198.8 27.6h5v2h-5zM222.9 25.4h5.1v8.9h-5.1zM225.4 29.2l.7 .7 .6-.7h1.3M228 26.7h-3.2v2.5l-.6 .7-.7-.7M244.7 28.6h2.1v5.1h-2.1zM252.1 30.1h5.1v2.1h-5.1zM269.5 35.6h2v5.1h-2zM276.2 23.5l10.2 5.1-10.2 5.1zM296.5 27.6h5.1v2h-5.1z"/>
<path d="M27.3 66.7h5.1v8.9h-5.1zM29.8 70.5l.7 .7 .6-.7h1.3M32.4 68h-3.2v2.5l-.6 .7-.7-.7M49.1 69.9h2.1v5.1h-2.1zM56.5 71.4h5.1v2h-5.1zM73.9 76.9h2v5.1h-2zM80.6 64.8l10.2 5.1-10.2 5.1zM100.3 68.9h5.1v2h-5.1zM125.1 66.7h5.1v8.9h-5.1zM127.6 70.5l.7 .7 .6-.7h1.3M130.2 68h-3.2v2.5l-.6 .7-.7-.7M146.9 69.9h2.1v5.1h-2.1z"/>
<path d="M154.3 71.4h5.1v2h-5.1zM171.7 76.9h2v5.1h-2zM178.4 64.8l10.2 5.1-10.2 5.1zM198.1 68.9h5.1v2h-5.1zM222.9 66.7h5.1v8.9h-5.1zM225.4 70.5l.7 .7 .6-.7h1.3M228 68h-3.2v2.5l-.6 .7-.7-.7M244.7 69.9h2.1v5.1h-2.1zM252.1 71.4h5.1v2h-5.1zM269.5 76.9h2v5.1h-2zM276.2 64.8l10.2 5.1-10.2 5.1zM295.9 68.9h5.1v2h-5.1z"/>
<path d="M26.7 115h5v8.9h-5zM29.2 118.8l.6 .6 .7-.6h1.2M31.7 116.2h-3.1v2.6l-.7 .6-.6-.6M48.5 118.1h2v5.1h-2zM55.9 119.7h5.1v2h-5.1zM80 113.1l10.2 5-10.2 5.1zM100.3 117.1h5.1v2.1h-5.1zM124.5 115h5v8.9h-5zM127 118.8l.6 .6 .7-.6h1.2M129.5 116.2h-3.1v2.6l-.7 .6-.6-.6M146.3 118.1h2v5.1h-2zM153.7 119.7h5v2h-5z"/>
<path d="M177.8 113.1l10.2 5-10.2 5.1zM198.1 117.1h5.1v2.1h-5.1zM222.2 115h5.1v8.9h-5.1zM224.8 118.8l.6 .6 .7-.6h1.2M227.3 116.2h-3.1v2.6l-.7 .6-.6-.6M244.1 118.1h2v5.1h-2zM251.5 119.7h5v2h-5zM275.6 113.1l10.1 5-10.1 5.1zM295.9 117.1h5.1v2.1h-5.1zM73.3 125.1h2v5.1h-2zM171.1 125.1h2v5.1h-2zM268.9 125.1h2v5.1h-2z"/>
<path d="M26.7 158.8h5v8.9h-5zM80 156.9l10.2 5.1-10.2 5zM124.5 158.8h5v8.9h-5zM177.8 156.9l10.2 5.1-10.2 5zM222.2 158.8h5.1v8.9h-5.1zM275.6 156.9l10.1 5.1-10.1 5zM29.2 162.6l.6 .6 .7-.6h1.2M31.7 160.1h-3.1v2.5l-.7 .6-.6-.6M48.5 162h2v5h-2zM55.9 163.5h5.1v2h-5.1zM73.3 168.9h2v5.1h-2zM100.3 160.9h5.1v2.1h-5.1z"/>
<path d="M127 162.6l.6 .6 .7-.6h1.2M129.5 160.1h-3.1v2.5l-.7 .6-.6-.6M146.3 162h2v5h-2zM153.7 163.5h5v2h-5zM171.1 168.9h2v5.1h-2zM198.1 160.9h5.1v2.1h-5.1zM224.8 162.6l.6 .6 .7-.6h1.2M227.3 160.1h-3.1v2.5l-.7 .6-.6-.6M244.1 162h2v5h-2zM251.5 163.5h5v2h-5zM268.9 168.9h2v5.1h-2zM295.9 160.9h5.1v2.1h-5.1z"/>
<path d="M200.7 214l10.1 5.1-10.1 5.1zM202.6 204.1h5v2.1h-5zM221.6 218.1h5.1v2h-5.1zM236.9 216.6l10.1 5.1-10.1 5zM240 206h5.1v2.1h-5.1zM257.2 220.6h5.1v2.1h-5.1zM272.4 220.4h5.1v8.9h-5.1zM272.4 224.2h1.3l.6 .6 .7-.6M272.4 221.7h3.2v2.5l.6 .6 .7-.6"/>
</g>
<g fill="#840000" stroke="#840000" stroke-width=".18">
<path d="M149.1 72.4l1.1-.5v1z"/>
<path d="M148.5 120.7l1.1-.5v1z"/>
<path d="M148.5 164.5l1.1-.5v1z"/>
<path d="M246.9 31.2l1.1-.6v1.1z"/>
<path d="M33.7 229.3v1.2h.7l-.7 1.3-.8-1.3h.8z"/>
<path d="M50.7 164.5l1.1-.5v1z"/>
<path d="M149.1 31.2l1.1-.6v1.1z"/>
<path d="M97.2 229.3v1.2h.7l-.7 1.3-.8-1.3h.8z"/>
<path d="M65.4 229.3v1.2h.8l-.8 1.3-.8-1.3h.8z"/>
<path d="M128.9 229.3v1.2h.8l-.8 1.3-.8-1.3h.8z"/>
<path d="M246.3 120.7l1.1-.5v1z"/>
<path d="M246.9 72.4l1.1-.5v1z"/>
<path d="M246.3 164.5l1.1-.5v1z"/>
<path d="M51.3 31.2l1.2-.6v1.1z"/>
<path d="M50.7 120.7l1.1-.5v1z"/>
<path d="M51.3 72.4l1.2-.5v1z"/>
</g>
<g fill="#ffffc2" stroke="#ffffc2" stroke-width=".18">
<path d="M125.1 66.7h5.1v8.9h-5.1z"/>
<path d="M124.5 115h5v8.9h-5z"/>
<path d="M124.5 158.8h5v8.9h-5z"/>
<path d="M276.2 23.5l10.2 5.1-10.2 5.1z"/>
<path d="M276.2 64.8l10.2 5.1-10.2 5.1z"/>
<path d="M275.6 113.1l10.1 5-10.1 5.1z"/>
<path d="M275.6 156.9l10.1 5.1-10.1 5z"/>
<path d="M26.7 158.8h5v8.9h-5z"/>
<path d="M222.9 25.4h5.1v8.9h-5.1z"/>
<path d="M178.4 23.5l10.2 5.1-10.2 5.1z"/>
<path d="M178.4 64.8l10.2 5.1-10.2 5.1z"/>
<path d="M177.8 113.1l10.2 5-10.2 5.1z"/>
<path d="M177.8 156.9l10.2 5.1-10.2 5z"/>
<path d="M125.1 25.4h5.1v8.9h-5.1z"/>
<path d="M222.9 66.7h5.1v8.9h-5.1z"/>
<path d="M80.6 64.8l10.2 5.1-10.2 5.1z"/>
<path d="M222.2 115h5.1v8.9h-5.1z"/>
<path d="M222.2 158.8h5.1v8.9h-5.1z"/>
<path d="M27.3 25.4h5.1v8.9h-5.1z"/>
<path d="M27.3 66.7h5.1v8.9h-5.1z"/>
<path d="M26.7 115h5v8.9h-5z"/>
<path d="M80.6 23.5l10.2 5.1-10.2 5.1z"/>
<path d="M272.4 220.4h5.1v8.9h-5.1z"/>
<path d="M236.9 216.6l10.1 5.1-10.1 5z"/>
<path d="M200.7 214l10.1 5.1-10.1 5.1z"/>
<path d="M80 113.1l10.2 5-10.2 5.1z"/>
<path d="M80 156.9l10.2 5.1-10.2 5z"/>
</g>
<g fill="#840000" stroke="#840000" stroke-width=".25">
<path d="M123.8 70.5h1.3v2.6h-1.3z"/>
<path d="M123.2 118.8h1.3v2.5h-1.3z"/>
<path d="M123.2 162.6h1.3v2.5h-1.3z"/>
<path d="M25.4 162.6h1.3v2.5h-1.3z"/>
<path d="M221.6 29.2h1.3v2.6h-1.3z"/>
<path d="M123.8 29.2h1.3v2.6h-1.3z"/>
<path d="M221.6 70.5h1.3v2.6h-1.3z"/>
<path d="M221 118.8h1.2v2.5h-1.2z"/>
<path d="M221 162.6h1.2v2.5h-1.2z"/>
<path d="M26 29.2h1.3v2.6h-1.3z"/>
<path d="M26 70.5h1.3v2.6h-1.3z"/>
<path d="M25.4 118.8h1.3v2.5h-1.3z"/>
<path d="M277.5 224.2h1.3v2.5h-1.3z"/>
</g>
<g fill="none" stroke="#008484" stroke-width=".18">
<path d="M39.1 22.6h.7M39.5 22.6v1.3M81.1 26.1h1M136.9 22.6h.7M137.3 22.6v1.3M178.9 26.1h1M234.7 22.6h.7M235.1 22.6v1.3M276.7 26.1h1M39.1 63.9h.7M39.5 63.9v1.3M81.1 67.4h1"/>
<path d="M136.9 63.9h.7M137.3 63.9v1.3M178.9 67.4h1M234.7 63.9h.7M235.1 63.9v1.3M276.7 67.4h1M38.5 112.2h.7M38.8 112.2v1.2M80.5 115.7h1M136.3 112.2h.7M136.6 112.2v1.2M178.3 115.7h1"/>
<path d="M234.1 112.2h.7M234.4 112.2v1.2M276.1 115.7h1M38.5 156h.7M38.8 156v1.3M80.5 159.5h1M136.3 156h.7M136.6 156v1.3M178.3 159.5h1M234.1 156h.7M234.4 156v1.3M276.1 159.5h1"/>
<path d="M42.5 218.6l1.2 .4-1.2 .4M43.3 217.2v.9M74.2 218.6l1.3 .4-1.3 .4M75 217.2v.9M106 218.6l1.2 .4-1.2 .4M106.8 217.2v.9M137.7 218.6l1.3 .4-1.3 .4M138.5 217.2v.9M201.1 216.6h1M237.3 219.2h1M297.4 225.2h.7M297.7 225.2v1.3"/>
</g>
<g fill="none" stroke="#0000c2" stroke-width=".18" stroke-dasharray=".4 .4">
<path d="M16.5 15.3h91.4M107.9 15.3v36.2M114.3 15.3h91.4M205.7 15.3v36.2M212.1 15.3h91.4M303.5 15.3v36.2M16.5 55.3h91.4M16.5 51.5v-36.2M107.9 55.3v38.7M107.9 51.5h-91.4M114.3 55.3h91.4M114.3 51.5v-36.2"/>
<path d="M205.7 55.3v38.7M205.7 51.5h-91.4M212.1 51.5v-36.2M212.1 55.3h91.4M303.5 51.5h-91.4M303.5 55.3v38.7M16.5 98.5h91.4M16.5 94v-38.7M107.9 98.5v44.4M107.9 94h-91.4M114.3 94v-38.7M114.3 98.5h91.4"/>
<path d="M205.7 94h-91.4M205.7 98.5v44.4M212.1 94v-38.7M212.1 98.5h91.4M303.5 94h-91.4M303.5 98.5v44.4M16.5 148h91.4M16.5 142.9v-44.4M107.9 148v38.7M107.9 142.9h-91.4M114.3 142.9v-44.4M114.3 148h91.4"/>
<path d="M205.7 142.9h-91.4M205.7 148v38.7M212.1 142.9v-44.4M212.1 148h91.4M303.5 142.9h-91.4M303.5 148v38.7M16.5 186.7v-38.7M16.5 193.7h131.5M107.9 186.7h-91.4M114.3 186.7v-38.7M148 193.7v47.6M182.2 198.2v43.1"/>
<path d="M205.7 186.7h-91.4M212.1 186.7v-38.7M302.9 198.2h-120.7M303.5 186.7h-91.4M16.5 241.3v-47.6M148 241.3h-131.5M182.2 241.3h120.7M302.9 241.3v-43.1"/>
</g>
<g fill="none" stroke="#008400" stroke-width=".18">
<path d="M34.9 26.7h15.3v.6M34.9 29.2h3.2v8.3M50.2 35v.6h-12.1M54 31.2h1.2M62.9 31.2h1.2M71.8 31.2h6.3M74.9 31.2v3.1M78.1 26.1h-1.3v-7h18.4v9.5M93.3 28.6h6.4M107.3 28.6h3.8v161.9h195.6v-161.9h-3.8M132.7 26.7h15.3v.6M132.7 29.2h3.2v8.3"/>
<path d="M148 35v.6h-12.1M151.8 31.2h1.2M160.7 31.2h1.2M169.5 31.2h6.4M172.7 31.2v3.1M175.9 26.1h-1.3v-7h18.4v9.5M191.1 28.6h6.4M205.1 28.6h3.8v161.9M230.5 29.2h3.2v8.3M230.5 26.7h15.2v.6M245.7 35v.6h-12M249.6 31.2h1.2"/>
<path d="M258.4 31.2h1.3M267.3 31.2h6.4M270.5 31.2v3.1M273.7 26.1h-1.3v-7h18.4v9.5M288.9 28.6h6.4M74.9 41.9v2M172.7 41.9v2M270.5 41.9v2M34.9 68h15.3v.6M34.9 70.5h3.2v8.3M50.2 76.2v.7h-12.1M54 72.4h1.2"/>
<path d="M62.9 72.4h1.2M71.8 72.4h6.3M74.9 72.4v3.2M78.1 67.3h-1.3v-6.9h18.4v9.5M93.3 69.9h5.8M106.7 69.9h4.4M132.7 68h15.3v.6M132.7 70.5h3.2v8.3M148 76.2v.7h-12.1M151.8 72.4h1.2M160.7 72.4h1.2M169.5 72.4h6.4"/>
<path d="M172.7 72.4v3.2M175.9 67.3h-1.3v-6.9h18.4v9.5M191.1 69.9h5.7M204.5 69.9h4.4M230.5 70.5h3.2v8.3M230.5 68h15.2v.6M245.7 76.2v.7h-12M249.6 72.4h1.2M258.4 72.4h1.3M267.3 72.4h6.4M270.5 72.4v3.2M273.7 67.3h-1.3v-6.9h18.4v9.5"/>
<path d="M288.9 69.9h5.7M302.3 69.9h4.4M74.9 83.2v1.9M172.7 83.2v1.9M270.5 83.2v1.9M34.3 116.2h15.2v.7M34.3 118.8h3.2v8.2M77.5 115.6h-1.3v-7h18.4v9.5M92.7 118.1h6.4M106.7 118.1h4.4M132.1 116.2h15.2v.7M132.1 118.8h3.2v8.2"/>
<path d="M175.3 115.6h-1.3v-7h18.4v9.5M190.5 118.1h6.3M204.5 118.1h4.4M229.9 116.2h15.2v.7M229.9 118.8h3.1v8.2M273 115.6h-1.2v-7h18.4v9.5M288.3 118.1h6.3M302.3 118.1h4.4M49.5 124.5v.6h-12M53.3 120.7h1.3M62.2 120.7h1.3M71.1 120.7h6.4"/>
<path d="M74.3 120.7v3.2M74.3 131.5v1.9M147.3 124.5v.6h-12M151.1 120.7h1.3M160 120.7h1.3M168.9 120.7h6.4M172.1 120.7v3.2M172.1 131.5v1.9M245.1 124.5v.6h-12.1M248.9 120.7h1.3M257.8 120.7h1.3M266.7 120.7h6.3"/>
<path d="M269.9 120.7v3.2M269.9 131.5v1.9M77.5 159.4h-1.3v-7h18.4v9.6M175.3 159.4h-1.3v-7h18.4v9.6M273 159.4h-1.2v-7h18.4v9.6M34.3 160.1h15.2v.6M34.3 162.6h3.2v8.3M49.5 168.3v.6h-12M53.3 164.5h1.3M62.2 164.5h1.3M71.1 164.5h6.4M74.3 164.5v3.2"/>
<path d="M74.3 175.3v1.9M92.7 162h6.4M106.7 162h4.4M132.1 160.1h15.2v.6M132.1 162.6h3.2v8.3M147.3 168.3v.6h-12M151.1 164.5h1.3M160 164.5h1.3M168.9 164.5h6.4M172.1 164.5v3.2M172.1 175.3v1.9M190.5 162h6.3"/>
<path d="M204.5 162h4.4M229.9 160.1h15.2v.6M229.9 162.6h3.1v8.3M245.1 168.3v.6h-12.1M248.9 164.5h1.3M257.8 164.5h1.3M266.7 164.5h6.3M269.9 164.5v3.2M269.9 175.3v1.9M288.3 162h6.3M302.3 162h4.4M180.3 190.5v26.1h17.8"/>
<path d="M24.8 206.4v-2.5h18.4v4.4M24.8 214v3.2M33.7 215.9h-13.4v8.3M33.7 201.3v5.1M33.7 214v3.2M56.5 206.4v-2.5h18.4v4.4M56.5 214v3.2M65.4 215.9h-13.3v8.3M65.4 201.3v5.1M65.4 214v3.2M88.3 206.4v-2.5h18.4v4.4M88.3 214v3.2"/>
<path d="M97.2 215.9h-13.4v8.3M97.2 201.3v5.1M97.2 214v3.2M120 206.4v-2.5h18.4v4.4M120 214v3.2M128.9 215.9h-13.3v8.3M128.9 201.3v5.1M128.9 214v3.2M201.3 205.1h-6.4v11.5M208.9 205.1h7.6v14M213.4 219.1h6.9M228 219.1h6.3"/>
<path d="M238.8 207h-7.7v12.1M246.4 207h7v14.7M33.7 224.8v4.5M43.2 223.6v3.8h-18.4v-2.6M65.4 224.8v4.5M74.9 223.6v3.8h-18.4v-2.6M97.2 224.8v4.5M106.7 223.6v3.8h-18.4v-2.6M128.9 224.8v4.5M138.4 223.6v3.8h-18.4v-2.6M198.1 221.7h-3.2v3.1M234.3 224.2h-3.2v3.8"/>
<path d="M249.6 221.7h6.3M263.5 221.7h6.4M269.9 224.2h-3.2v6.3"/>
</g>
<path d="M30 237.8v1.1l.2 .2M30.6 238.3l.3 .8M31.2 238.3l-.4 1.1-.2 .1" fill="none" stroke="#0000c2" stroke-width=".18"/>
<g fill="#008400" stroke="#008400" stroke-width=".25">
<circle cx="270.5" cy="72.4" r=".51"/>
<circle cx="97.2" cy="215.9" r=".51"/>
<circle cx="270.5" cy="31.2" r=".51"/>
<circle cx="192.4" cy="162" r=".51"/>
<circle cx="128.9" cy="215.9" r=".51"/>
<circle cx="94.6" cy="162" r=".51"/>
<circle cx="233.7" cy="76.9" r=".51"/>
<circle cx="88.3" cy="215.9" r=".51"/>
<circle cx="74.3" cy="120.7" r=".51"/>
<circle cx="233.7" cy="35.6" r=".51"/>
<circle cx="120" cy="215.9" r=".51"/>
<circle cx="290.8" cy="28.6" r=".51"/>
<circle cx="37.5" cy="168.9" r=".51"/>
<circle cx="128.9" cy="227.4" r=".51"/>
<circle cx="97.2" cy="227.4" r=".51"/>
<circle cx="128.9" cy="203.9" r=".51"/>
<circle cx="74.3" cy="164.5" r=".51"/>
<circle cx="290.8" cy="69.9" r=".51"/>
<circle cx="253.4" cy="221.7" r=".51"/>
<circle cx="37.5" cy="125.1" r=".51"/>
<circle cx="94.6" cy="118.1" r=".51"/>
<circle cx="97.2" cy="203.9" r=".51"/>
<circle cx="231.1" cy="219.1" r=".51"/>
<circle cx="172.7" cy="31.2" r=".51"/>
<circle cx="192.4" cy="118.1" r=".51"/>
<circle cx="233" cy="168.9" r=".51"/>
<circle cx="193" cy="28.6" r=".51"/>
<circle cx="33.7" cy="215.9" r=".51"/>
<circle cx="208.9" cy="69.9" r=".51"/>
<circle cx="208.9" cy="118.1" r=".51"/>
<circle cx="172.1" cy="120.7" r=".51"/>
<circle cx="95.2" cy="28.6" r=".51"/>
<circle cx="180.3" cy="190.5" r=".51"/>
<circle cx="269.9" cy="164.5" r=".51"/>
<circle cx="135.3" cy="125.1" r=".51"/>
<circle cx="208.9" cy="190.5" r=".51"/>
<circle cx="194.9" cy="216.6" r=".51"/>
<circle cx="135.9" cy="76.9" r=".51"/>
<circle cx="38.1" cy="76.9" r=".51"/>
<circle cx="306.7" cy="162" r=".51"/>
<circle cx="306.7" cy="118.1" r=".51"/>
<circle cx="111.1" cy="69.9" r=".51"/>
<circle cx="306.7" cy="69.9" r=".51"/>
<circle cx="208.9" cy="162" r=".51"/>
<circle cx="111.1" cy="162" r=".51"/>
<circle cx="111.1" cy="118.1" r=".51"/>
<circle cx="56.5" cy="215.9" r=".51"/>
<circle cx="38.1" cy="35.6" r=".51"/>
<circle cx="172.1" cy="164.5" r=".51"/>
<circle cx="233" cy="125.1" r=".51"/>
<circle cx="74.9" cy="72.4" r=".51"/>
<circle cx="65.4" cy="227.4" r=".51"/>
<circle cx="65.4" cy="203.9" r=".51"/>
<circle cx="24.8" cy="215.9" r=".51"/>
<circle cx="216.5" cy="219.1" r=".51"/>
<circle cx="95.3" cy="69.9" r=".51"/>
<circle cx="65.4" cy="215.9" r=".51"/>
<circle cx="193" cy="69.9" r=".51"/>
<circle cx="135.9" cy="35.6" r=".51"/>
<circle cx="135.3" cy="168.9" r=".51"/>
<circle cx="172.7" cy="72.4" r=".51"/>
<circle cx="269.9" cy="120.7" r=".51"/>
<circle cx="290.2" cy="118.1" r=".51"/>
<circle cx="290.2" cy="162" r=".51"/>
<circle cx="33.7" cy="227.4" r=".51"/>
<circle cx="33.7" cy="203.9" r=".51"/>
<circle cx="74.9" cy="31.2" r=".51"/>
</g>
<g fill="none" stroke="#000084" stroke-width=".18">
<path d="M34.3 31.2l1.2 1.2M35.5 31.2l-1.2 1.2M132.1 31.2l1.2 1.2M133.3 31.2l-1.2 1.2M229.9 31.2l1.2 1.2M231.1 31.2l-1.2 1.2M34.3 72.5l1.2 1.2M35.5 72.5l-1.2 1.2M132.1 72.5l1.2 1.2M133.3 72.5l-1.2 1.2M229.9 72.5l1.2 1.2M231.1 72.5l-1.2 1.2"/>
<path d="M33.7 120.7l1.2 1.2M34.9 120.7l-1.2 1.2M131.5 120.7l1.2 1.2M132.7 120.7l-1.2 1.2M229.3 120.7l1.2 1.2M230.5 120.7l-1.2 1.2M33.7 164.5l1.2 1.2M34.9 164.5l-1.2 1.2M131.5 164.5l1.2 1.2M132.7 164.5l-1.2 1.2M229.3 164.5l1.2 1.2M230.5 164.5l-1.2 1.2"/>
<path d="M269.3 226.1l1.2 1.2M270.5 226.1l-1.2 1.2"/>
</g>
<use href="#words"/>
</svg>
